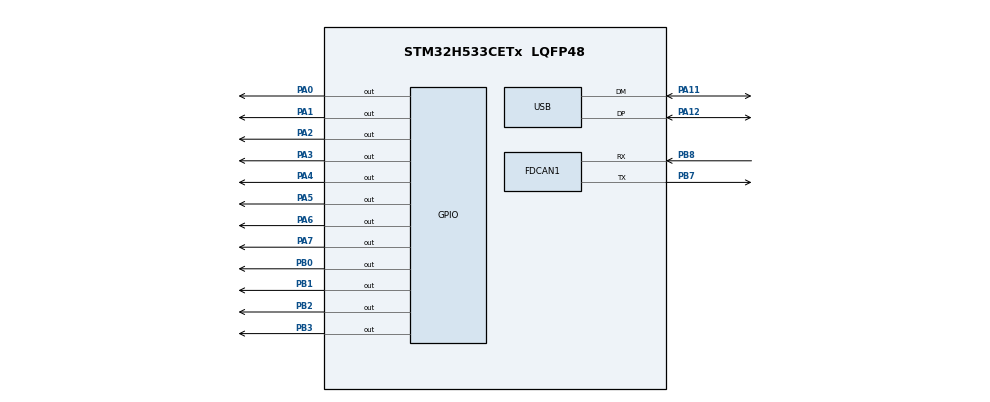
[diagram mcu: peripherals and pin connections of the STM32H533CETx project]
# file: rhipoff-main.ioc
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CORTEX_M33_NS.userName=CORTEX_M33
FDCAN1.CalculateBaudRateNominal=5208333
FDCAN1.CalculateTimeBitNominal=192
FDCAN1.CalculateTimeQuantumNominal=64.0
Mcu.Family=STM32H5
Mcu.Name=STM32H533CETx
Mcu.Package=LQFP48
NVIC.PriorityGroup=NVIC_PRIORITYGROUP_4
NVIC.USB_DRD_FS_IRQn=true\:0\:0\:false\:false\:true\:true\:true\:true
PA0.Signal=GPIO_Output
PA1.Signal=GPIO_Output
PA11.Mode=Device
PA11.Signal=USB_DM
PA12.Mode=Device
PA12.Signal=USB_DP
PA13(JTMS/SWDIO).Signal=DEBUG_JTMS-SWDIO
PA14(JTCK/SWCLK).Signal=DEBUG_JTCK-SWCLK
PA2.Signal=GPIO_Output
PA3.Signal=GPIO_Output
PA4.Signal=GPIO_Output
PA5.Signal=GPIO_Output
PA6.Signal=GPIO_Output
PA7.Signal=GPIO_Output
PB0.Signal=GPIO_Output
PB1.Signal=GPIO_Output
PB2.Signal=GPIO_Output
PB3(JTDO/TRACESWO).Signal=GPIO_Output
PB7.Mode=FDCAN_Activate
PB7.Signal=FDCAN1_TX
PB8.Mode=FDCAN_Activate
PB8.Signal=FDCAN1_RX
ProjectManager.HeapSize=0x600
ProjectManager.StackSize=0x700
ProjectManager.TargetToolchain=STM32CubeIDE
RCC.ADCFreq_Value=250000000
RCC.AHBFreq_Value=250000000
RCC.APB1Freq_Value=250000000
RCC.APB1TimFreq_Value=250000000
RCC.APB2Freq_Value=250000000
RCC.APB2TimFreq_Value=250000000
RCC.APB3Freq_Value=250000000
RCC.CSI_VALUE=4000000
RCC.CortexFreq_Value=250000000
RCC.EPOD_VALUE=4000000
RCC.FDCANClockSelection=RCC_FDCANCLKSOURCE_PLL1Q
RCC.HCLKFreq_Value=250000000
RCC.HSE_VALUE=25000000
RCC.HSI48_VALUE=48000000
RCC.HSI_VALUE=64000000
RCC.LSE_VALUE=32768
RCC.LSIRC_VALUE=32000
RCC.PLL2FRACN=0
RCC.PLL3FRACN=0
RCC.PLLFRACN=0
RCC.PLLN=125
RCC.SYSCLKFreq_VALUE=250000000
RCC.SYSCLKSource=RCC_SYSCLKSOURCE_PLLCLK
RCC.USBFreq_Value=48000000
RCC.VCOOutputFreq_Value=500000000
USB.VirtualMode=Device_Only
VP_BOOTPATH_VS_BOOTPATH.Mode=BP_Activate
VP_CORTEX_M33_NS_VS_Hclk.Mode=Hclk_Mode
VP_MEMORYMAP_VS_MEMORYMAP.Mode=CurAppReg
VP_PWR_VS_DBSignals.Mode=DisableDeadBatterySignals
VP_PWR_VS_LPOM.Mode=PowerOptimisation
VP_PWR_VS_SECSignals.Mode=Security/Privilege
board=custom

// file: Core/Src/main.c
/* USER CODE BEGIN Header */
/**
  ******************************************************************************
  * @file           : main.c
  * @brief          : Main program body
  ******************************************************************************
  * @attention
  *
  * Copyright (c) 2024 STMicroelectronics.
  * All rights reserved.
  *
  * This software is licensed under terms that can be found in the LICENSE file
  * in the root directory of this software component.
  * If no LICENSE file comes with this software, it is provided AS-IS.
  *
  ******************************************************************************
  */
/* USER CODE END Header */
#include "main.h"

/* USER CODE BEGIN Includes */
#include "usbd_core.h"
#include "usbd_cdc.h"
#include "usbd_cdc_if.h"
#include "usbd_customhid.h"
#include "usbd_customhid_if.h"
#include "usbd_desc.h"
#include "usbd_composite_builder.h"
/* USER CODE END Includes */

FDCAN_HandleTypeDef hfdcan1;

PCD_HandleTypeDef hpcd_USB_DRD_FS;

/* USER CODE BEGIN PV */
uint8_t CDC_EpAdd_Inst[3] = {CDC_IN_EP, CDC_OUT_EP, CDC_CMD_EP}; 	/* CDC Endpoint Addresses array */
uint8_t CUSTOM_HID_EpAdd_Inst[2] = {CUSTOM_HID_EPIN_ADDR, CUSTOM_HID_EPOUT_ADDR};		/* HID Endpoint Address array */
USBD_HandleTypeDef hUsbDeviceFS;
uint8_t CHID_InstID = 0, CDC_InstID = 0;

FDCAN_RxHeaderTypeDef Rx_Header;
uint8_t rxData[8];
FDCAN_TxHeaderTypeDef Tx_Header;
uint8_t txData[4];
char buffer[256]; // :)
uint8_t buttons[2] = {0};
/* USER CODE END PV */

void SystemClock_Config(void);
static void MX_GPIO_Init(void);
static void MX_FDCAN1_Init(void);
/* USER CODE BEGIN PFP */
static void FDCAN_Config(void);
/* USER CODE END PFP */

int main(void)
{

  /* MCU Configuration--------------------------------------------------------*/

  /* Reset of all peripherals, Initializes the Flash interface and the Systick. */
  HAL_Init();

  /* Configure the system clock */
  SystemClock_Config();

  /* Initialize all configured peripherals */
  MX_GPIO_Init();
  MX_FDCAN1_Init();
  /* USER CODE BEGIN 2 */
  /* Initialize the USB Device Library */
  if(USBD_Init(&hUsbDeviceFS, &Class_Desc, 0) != USBD_OK)
  	Error_Handler();
  /* Register the CHID Class */
  CHID_InstID = hUsbDeviceFS.classId;
  if(USBD_RegisterClassComposite(&hUsbDeviceFS, USBD_CUSTOM_HID_CLASS, CLASS_TYPE_CHID, CUSTOM_HID_EpAdd_Inst) != USBD_OK)
  	Error_Handler();
    /* Register CDC Class First Instance */
  CDC_InstID = hUsbDeviceFS.classId;
  if(USBD_RegisterClassComposite(&hUsbDeviceFS, USBD_CDC_CLASS, CLASS_TYPE_CDC, CDC_EpAdd_Inst) != USBD_OK)
  	Error_Handler();
/* Store Instance Class ID */
  if (USBD_CMPSIT_SetClassID(&hUsbDeviceFS, CLASS_TYPE_CHID, 0) != 0xFF)
  {
    USBD_CUSTOM_HID_RegisterInterface(&hUsbDeviceFS, &USBD_CustomHID_template_fops);
  }
  if (USBD_CMPSIT_SetClassID(&hUsbDeviceFS, CLASS_TYPE_CDC, 0) != 0xFF)
  {
  	USBD_CDC_RegisterInterface(&hUsbDeviceFS, &USBD_CDC_Template_fops);
  }
  /* Add CHID Interface Class */
  USBD_Start(&hUsbDeviceFS);

  FDCAN_Config(); // need to set up the FD CAN peripheral with our parameters.

  /* USER CODE END 2 */

  /* Infinite loop */
  /* USER CODE BEGIN WHILE */
  while (1)
  {
  		USBD_CDC_TransmitPacket(&hUsbDeviceFS, CDC_InstID);
  		HAL_GPIO_WritePin(GPIOA, GPIO_PIN_0, GPIO_PIN_SET);
  		if (HAL_FDCAN_AddMessageToTxFifoQ(&hfdcan1, &Tx_Header, txData) != HAL_OK) // not useful rn
  		{
  			Error_Handler();
  		}
  		HAL_Delay(50);

  	    sprintf(buffer, "%d %d %d %d\r\n", rxData[0], rxData[1], rxData[2], rxData[3]);
  	    	buttons[0] = ((rxData[0] > 75) + 2*(rxData[1] > 75) + 4*(rxData[2] > 75) + 8*(rxData[3] > 75));
  	    USBD_CUSTOM_HID_SendReport(&hUsbDeviceFS, buttons, sizeof(buttons), CHID_InstID);
    /* USER CODE END WHILE */

  }
}
void SystemClock_Config(void)
{
  RCC_OscInitTypeDef RCC_OscInitStruct = {0};
  RCC_ClkInitTypeDef RCC_ClkInitStruct = {0};

  /** Configure the main internal regulator output voltage
  */
  __HAL_PWR_VOLTAGESCALING_CONFIG(PWR_REGULATOR_VOLTAGE_SCALE0);

  while(!__HAL_PWR_GET_FLAG(PWR_FLAG_VOSRDY)) {}

  /** Initializes the RCC Oscillators according to the specified parameters
  * in the RCC_OscInitTypeDef structure.
  */
  RCC_OscInitStruct.OscillatorType = RCC_OSCILLATORTYPE_HSI48|RCC_OSCILLATORTYPE_CSI;
  RCC_OscInitStruct.HSI48State = RCC_HSI48_ON;
  RCC_OscInitStruct.CSIState = RCC_CSI_ON;
  RCC_OscInitStruct.CSICalibrationValue = RCC_CSICALIBRATION_DEFAULT;
  RCC_OscInitStruct.PLL.PLLState = RCC_PLL_ON;
  RCC_OscInitStruct.PLL.PLLSource = RCC_PLL1_SOURCE_CSI;
  RCC_OscInitStruct.PLL.PLLM = 1;
  RCC_OscInitStruct.PLL.PLLN = 120;
  RCC_OscInitStruct.PLL.PLLP = 2;
  RCC_OscInitStruct.PLL.PLLQ = 2;
  RCC_OscInitStruct.PLL.PLLR = 2;
  RCC_OscInitStruct.PLL.PLLRGE = RCC_PLL1_VCIRANGE_2;
  RCC_OscInitStruct.PLL.PLLVCOSEL = RCC_PLL1_VCORANGE_WIDE;
  RCC_OscInitStruct.PLL.PLLFRACN = 0;
  if (HAL_RCC_OscConfig(&RCC_OscInitStruct) != HAL_OK)
  {
    Error_Handler();
  }

  /** Initializes the CPU, AHB and APB buses clocks
  */
  RCC_ClkInitStruct.ClockType = RCC_CLOCKTYPE_HCLK|RCC_CLOCKTYPE_SYSCLK
                              |RCC_CLOCKTYPE_PCLK1|RCC_CLOCKTYPE_PCLK2
                              |RCC_CLOCKTYPE_PCLK3;
  RCC_ClkInitStruct.SYSCLKSource = RCC_SYSCLKSOURCE_PLLCLK;
  RCC_ClkInitStruct.AHBCLKDivider = RCC_SYSCLK_DIV1;
  RCC_ClkInitStruct.APB1CLKDivider = RCC_HCLK_DIV1;
  RCC_ClkInitStruct.APB2CLKDivider = RCC_HCLK_DIV1;
  RCC_ClkInitStruct.APB3CLKDivider = RCC_HCLK_DIV1;

  if (HAL_RCC_ClockConfig(&RCC_ClkInitStruct, FLASH_LATENCY_5) != HAL_OK)
  {
    Error_Handler();
  }

  /** Configure the programming delay
  */
  __HAL_FLASH_SET_PROGRAM_DELAY(FLASH_PROGRAMMING_DELAY_2);
}

static void MX_FDCAN1_Init(void)
{

  hfdcan1.Instance = FDCAN1;
  hfdcan1.Init.ClockDivider = FDCAN_CLOCK_DIV1;
  hfdcan1.Init.FrameFormat = FDCAN_FRAME_CLASSIC;
  hfdcan1.Init.Mode = FDCAN_MODE_NORMAL;
  hfdcan1.Init.AutoRetransmission = DISABLE;
  hfdcan1.Init.TransmitPause = DISABLE;
  hfdcan1.Init.ProtocolException = DISABLE;
  hfdcan1.Init.NominalPrescaler = 15;
  hfdcan1.Init.NominalSyncJumpWidth = 2;
  hfdcan1.Init.NominalTimeSeg1 = 13;
  hfdcan1.Init.NominalTimeSeg2 = 2;
  hfdcan1.Init.DataPrescaler = 15;
  hfdcan1.Init.DataSyncJumpWidth = 2;
  hfdcan1.Init.DataTimeSeg1 = 13;
  hfdcan1.Init.DataTimeSeg2 = 2;
  hfdcan1.Init.StdFiltersNbr = 1;
  hfdcan1.Init.ExtFiltersNbr = 0;
  hfdcan1.Init.TxFifoQueueMode = FDCAN_TX_FIFO_OPERATION;
  if (HAL_FDCAN_Init(&hfdcan1) != HAL_OK)
  {
    Error_Handler();
  }

}

void MX_USB_PCD_Init(void)
{

  hpcd_USB_DRD_FS.Instance = USB_DRD_FS;
  hpcd_USB_DRD_FS.Init.dev_endpoints = 8;
  hpcd_USB_DRD_FS.Init.speed = USBD_FS_SPEED;
  hpcd_USB_DRD_FS.Init.phy_itface = PCD_PHY_EMBEDDED;
  hpcd_USB_DRD_FS.Init.Sof_enable = DISABLE;
  hpcd_USB_DRD_FS.Init.low_power_enable = DISABLE;
  hpcd_USB_DRD_FS.Init.lpm_enable = DISABLE;
  hpcd_USB_DRD_FS.Init.battery_charging_enable = DISABLE;
  hpcd_USB_DRD_FS.Init.vbus_sensing_enable = DISABLE;
  hpcd_USB_DRD_FS.Init.bulk_doublebuffer_enable = DISABLE;
  hpcd_USB_DRD_FS.Init.iso_singlebuffer_enable = DISABLE;
  if (HAL_PCD_Init(&hpcd_USB_DRD_FS) != HAL_OK)
  {
    Error_Handler();
  }

}

static void MX_GPIO_Init(void)
{
  GPIO_InitTypeDef GPIO_InitStruct = {0};

  /* GPIO Ports Clock Enable */
  __HAL_RCC_GPIOA_CLK_ENABLE();
  __HAL_RCC_GPIOB_CLK_ENABLE();

  /*Configure GPIO pin Output Level */
  HAL_GPIO_WritePin(GPIOA, GPIO_PIN_0|GPIO_PIN_1|GPIO_PIN_2|GPIO_PIN_3
                          |GPIO_PIN_4|GPIO_PIN_5|GPIO_PIN_6|GPIO_PIN_7, GPIO_PIN_RESET);

  /*Configure GPIO pin Output Level */
  HAL_GPIO_WritePin(GPIOB, GPIO_PIN_0|GPIO_PIN_1|GPIO_PIN_2|GPIO_PIN_3, GPIO_PIN_RESET);

  /*Configure GPIO pins : PA0 PA1 PA2 PA3
                           PA4 PA5 PA6 PA7 */
  GPIO_InitStruct.Pin = GPIO_PIN_0|GPIO_PIN_1|GPIO_PIN_2|GPIO_PIN_3
                          |GPIO_PIN_4|GPIO_PIN_5|GPIO_PIN_6|GPIO_PIN_7;
  GPIO_InitStruct.Mode = GPIO_MODE_OUTPUT_PP;
  GPIO_InitStruct.Pull = GPIO_NOPULL;
  GPIO_InitStruct.Speed = GPIO_SPEED_FREQ_LOW;
  HAL_GPIO_Init(GPIOA, &GPIO_InitStruct);

  /*Configure GPIO pins : PB0 PB1 PB2 PB3 */
  GPIO_InitStruct.Pin = GPIO_PIN_0|GPIO_PIN_1|GPIO_PIN_2|GPIO_PIN_3;
  GPIO_InitStruct.Mode = GPIO_MODE_OUTPUT_PP;
  GPIO_InitStruct.Pull = GPIO_NOPULL;
  GPIO_InitStruct.Speed = GPIO_SPEED_FREQ_LOW;
  HAL_GPIO_Init(GPIOB, &GPIO_InitStruct);

}

/* USER CODE BEGIN 4 */
static void FDCAN_Config(void)
{
	FDCAN_FilterTypeDef filter;

	filter.IdType = FDCAN_STANDARD_ID;
	filter.FilterIndex = 0;
	filter.FilterType = FDCAN_FILTER_RANGE;
	filter.FilterConfig = FDCAN_FILTER_TO_RXFIFO0;
	filter.FilterID1 = 0x0;
	filter.FilterID2 = 0x7FF;

	if (HAL_FDCAN_ConfigFilter(&hfdcan1, &filter) != HAL_OK)
	  {
	    Error_Handler();
	  }

	if (HAL_FDCAN_ConfigGlobalFilter(&hfdcan1, FDCAN_REJECT, FDCAN_REJECT, FDCAN_FILTER_REMOTE, FDCAN_FILTER_REMOTE) != HAL_OK)
	  {
	    Error_Handler();
	  }

	if (HAL_FDCAN_Start(&hfdcan1) != HAL_OK)
	  {
	    Error_Handler();
	  }

	  if (HAL_FDCAN_ActivateNotification(&hfdcan1, FDCAN_IT_RX_FIFO0_NEW_MESSAGE, 0) != HAL_OK)
	  {
	    Error_Handler();
	  }

	  Tx_Header.Identifier = 0x23D;
	  Tx_Header.IdType = FDCAN_STANDARD_ID;
	  Tx_Header.TxFrameType = FDCAN_DATA_FRAME;
	  Tx_Header.DataLength = FDCAN_DLC_BYTES_4;
	  Tx_Header.ErrorStateIndicator = FDCAN_ESI_ACTIVE;
	  Tx_Header.BitRateSwitch = FDCAN_BRS_OFF;
	  Tx_Header.FDFormat = FDCAN_CLASSIC_CAN;
	  Tx_Header.TxEventFifoControl = FDCAN_NO_TX_EVENTS;
	  Tx_Header.MessageMarker = 0;
}

void HAL_FDCAN_RxFifo0Callback(FDCAN_HandleTypeDef *hfdcan, uint32_t RxFifo0ITs)
{
	if (RxFifo0ITs == FDCAN_IT_RX_FIFO0_NEW_MESSAGE) // we have a new message!
	{
		if (HAL_FDCAN_GetRxMessage(&hfdcan1, FDCAN_RX_FIFO0, &Rx_Header, rxData) != HAL_OK)
		{
			Error_Handler();
		}
	}
}

/* USER CODE END 4 */

void Error_Handler(void)
{
  __disable_irq();
  while (1)
  {
  }
}
